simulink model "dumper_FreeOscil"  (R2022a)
settings: Solver=VariableStepAuto  StartTime=0.0  StopTime=10.0  RelTol=1e-3
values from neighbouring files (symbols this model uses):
  c = [zeta(1)*(2*m*w);           zeta(2)*(2*m*w);           zeta(3)*(2*m*w)]    [FreeOscil_Displace_Test01.m]
  k = 9e9    (= 9000000000)    [electDipole.m]    (also in solvGasSei.m = 1; solvJacobi.m = 1; solvSOR.m = 1; solvSORerr.m = 1)
  m = 4*m    (= 4)    [rom_int.m]    (also in FreeOscil_Displace_Test01.m = 1; vspring.m = 1)

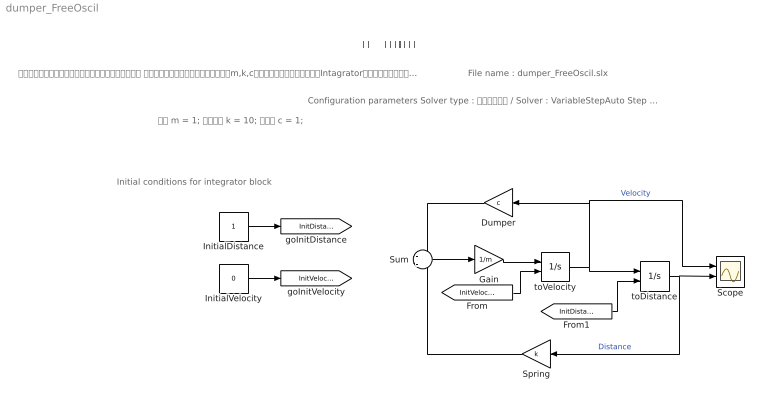
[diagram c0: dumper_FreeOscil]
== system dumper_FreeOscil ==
  note: Initial conditions for integrator block
  note: Configuration parameters Solver type : 可変ステップ / Solver : VariableStepAuto Step size : auto
  note: 質量 m = 1; ばね係数 k = 10; 減衰率 c = 1;
  note: File name : dumper_FreeOscil.slx
  note: 減衰項（ダンバー）を含んだマス－ばねの振動モデル シミュレーションはモデルパラメータm,k,cをワークスペースに設定し，Intagratorブロックの初期条件値を設定しておく
  note: 減衰項を含んだ振動系モデル
  Dumper : Gain  Gain=c
  Gain : Gain  Gain=1/m
  InitialDistance : Constant
  InitialVelocity : Constant  Value=0
  Scope : Scope  NumInputPorts=2
  Spring : Gain  Gain=k
  Sum : Sum  Inputs=-|-
  toDistance : Integrator  InitialConditionSource=external
  toVelocity : Integrator  InitialConditionSource=external
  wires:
  InitialDistance/1 -> [InitDistance]
  InitialVelocity/1 -> [InitVelocity]
  Gain/1 -> toVelocity/1
  [InitVelocity] -> toVelocity/2
  [InitDistance] -> toDistance/2
  toVelocity/1 -> Dumper/1, Scope/1, toDistance/1  "Velocity"
  Sum/1 -> Gain/1
  Dumper/1 -> Sum/1
  Spring/1 -> Sum/2
  toDistance/1 -> Spring/1, Scope/2  "Distance"
